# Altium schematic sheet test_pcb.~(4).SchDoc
size A4; SheetNumber: 1; SheetTotal: 1

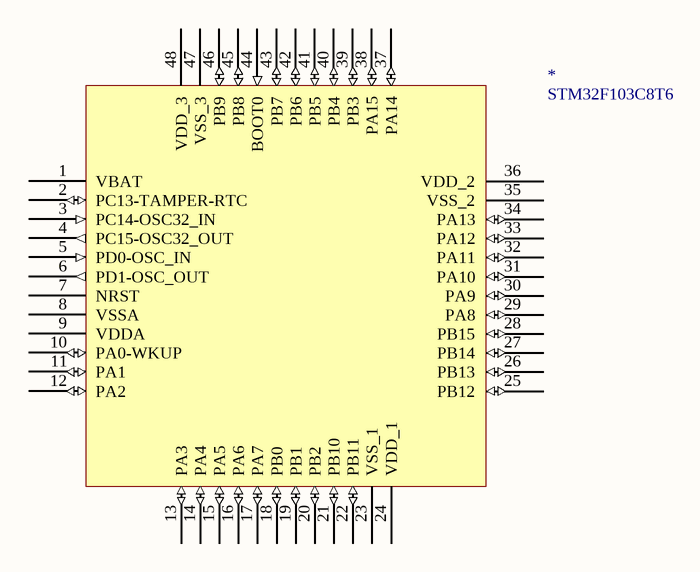
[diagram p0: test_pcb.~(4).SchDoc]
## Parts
*  STM32F103C8T6

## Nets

Not connected (* = marked no-connect by the designer): * 1(VBAT) 2(PC13-TAMPER-RTC) 3(PC14-OSC32_IN) 4(PC15-OSC32_OUT) 5(PD0-OSC_IN) 6(PD1-OSC_OUT) 7(NRST) 8(VSSA) 9(VDDA) 10(PA0-WKUP) 11(PA1) 12(PA2) 13(PA3) 14(PA4) 15(PA5) 16(PA6) 17(PA7) 18(PB0) 19(PB1) 20(PB2) 21(PB10) 22(PB11) 23(VSS_1) 24(VDD_1) 25(PB12) 26(PB13) 27(PB14) 28(PB15) 29(PA8) 30(PA9) 31(PA10) 32(PA11) 33(PA12) 34(PA13) 35(VSS_2) 36(VDD_2) 37(PA14) 38(PA15) 39(PB3) 40(PB4) 41(PB5) 42(PB6) 43(PB7) 44(BOOT0) 45(PB8) 46(PB9) 47(VSS_3) 48(VDD_3)

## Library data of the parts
* = STM32F103C8T6: ARM Cortex-M3 STM32 F1 Microcontroller 32-Bit 72MHz 64kB FLASH LQFP48 STM32F103C8T6; Manufacturer: STMicroelectronics; Package Body Material: Plastic; Clock Frequency: 16MHz; Number of I/O Lines: 37; Package Equivalence Code: QFP48,.35SQ,20; Power Supplies: 2.5/3.3; Max Supply Current: 50mA; Max Supply Voltage: 3.6V; Min Supply Voltage: 2V; Nominal Supply Voltage: 3.3V; Time @ Peak Reflow Temperature-Max (s): 30s; Peripherals: POR; Interface: I2C; Qualification Status: Not Qualified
